VERSION 5.8 ;
BUSBITCHARS "[]" ;
DIVIDERCHAR "/" ;

VIA PYL1_C_0
  VIARULE PYL1_C ;
  CUTSIZE 0.17 0.17 ;
  LAYERS poly licon1 li1 ;
  CUTSPACING 0.17 0.17 ;
  ENCLOSURE 0.08 0.08 0.08 0.08 ;
  ROWCOL 1 1 ;
END PYL1_C_0

VIA PYL1_C_1
  VIARULE PYL1_C ;
  CUTSIZE 0.17 0.17 ;
  LAYERS poly licon1 li1 ;
  CUTSPACING 0.17 0.17 ;
  ENCLOSURE 0.08 0.08 0.08 0.08 ;
  ROWCOL 1 23 ;
END PYL1_C_1

VIA PYL1_C_2
  VIARULE PYL1_C ;
  CUTSIZE 0.17 0.17 ;
  LAYERS poly licon1 li1 ;
  CUTSPACING 0.17 0.17 ;
  ENCLOSURE 0.08 0.08 0.08 0.08 ;
  ROWCOL 1 7 ;
END PYL1_C_2

VIA PYL1_C_3
  VIARULE PYL1_C ;
  CUTSIZE 0.17 0.17 ;
  LAYERS poly licon1 li1 ;
  CUTSPACING 0.17 0.17 ;
  ENCLOSURE 0.08 0.08 0.08 0.08 ;
  ROWCOL 1 17 ;
END PYL1_C_3

VIA PYL1_C_4
  VIARULE PYL1_C ;
  CUTSIZE 0.17 0.17 ;
  LAYERS poly licon1 li1 ;
  CUTSPACING 0.17 0.17 ;
  ENCLOSURE 0.08 0.08 0.08 0.08 ;
  ROWCOL 1 21 ;
END PYL1_C_4

VIA PYL1_C_5
  VIARULE PYL1_C ;
  CUTSIZE 0.17 0.17 ;
  LAYERS poly licon1 li1 ;
  CUTSPACING 0.17 0.17 ;
  ENCLOSURE 0.08 0.08 0.08 0.08 ;
  ROWCOL 1 8 ;
END PYL1_C_5

VIA PYL1_C_6
  VIARULE PYL1_C ;
  CUTSIZE 0.17 0.17 ;
  LAYERS poly licon1 li1 ;
  CUTSPACING 0.17 0.17 ;
  ENCLOSURE 0.08 0.08 0.08 0.08 ;
  ROWCOL 1 10 ;
END PYL1_C_6

VIA PYL1_C_7
  VIARULE PYL1_C ;
  CUTSIZE 0.17 0.17 ;
  LAYERS poly licon1 li1 ;
  CUTSPACING 0.17 0.17 ;
  ENCLOSURE 0.08 0.08 0.08 0.08 ;
  ROWCOL 1 6 ;
END PYL1_C_7

VIA PYL1_C_8
  VIARULE PYL1_C ;
  CUTSIZE 0.17 0.17 ;
  LAYERS poly licon1 li1 ;
  CUTSPACING 0.17 0.17 ;
  ENCLOSURE 0.08 0.08 0.08 0.08 ;
  ROWCOL 1 1 ;
END PYL1_C_8

VIA PYL1_C_9
  VIARULE PYL1_C ;
  CUTSIZE 0.17 0.17 ;
  LAYERS poly licon1 li1 ;
  CUTSPACING 0.17 0.17 ;
  ENCLOSURE 0.08 0.08 0.08 0.08 ;
  ROWCOL 1 3 ;
END PYL1_C_9

VIA PYL1_C_10
  VIARULE PYL1_C ;
  CUTSIZE 0.17 0.17 ;
  LAYERS poly licon1 li1 ;
  CUTSPACING 0.19 0.19 ;
  ENCLOSURE 0.08 0.08 0.08 0.08 ;
  ROWCOL 1 2 ;
END PYL1_C_10

VIA PYL1_C_11
  VIARULE PYL1_C ;
  CUTSIZE 0.17 0.17 ;
  LAYERS poly licon1 li1 ;
  CUTSPACING 0.17 0.17 ;
  ENCLOSURE 0.08 0.08 0.08 0.08 ;
  ROWCOL 1 5 ;
END PYL1_C_11

VIA PYL1_C_12
  VIARULE PYL1_C ;
  CUTSIZE 0.17 0.17 ;
  LAYERS poly licon1 li1 ;
  CUTSPACING 0.17 0.17 ;
  ENCLOSURE 0.08 0.08 0.08 0.08 ;
  ROWCOL 1 14 ;
END PYL1_C_12

VIA PYL1_C_13
  VIARULE PYL1_C ;
  CUTSIZE 0.17 0.17 ;
  LAYERS poly licon1 li1 ;
  CUTSPACING 0.17 0.17 ;
  ENCLOSURE 0.08 0.08 0.08 0.08 ;
  ROWCOL 1 90 ;
END PYL1_C_13

VIA PYL1_C_14
  VIARULE PYL1_C ;
  CUTSIZE 0.17 0.17 ;
  LAYERS poly licon1 li1 ;
  CUTSPACING 0.17 0.17 ;
  ENCLOSURE 0.08 0.08 0.08 0.08 ;
  ROWCOL 1 4 ;
END PYL1_C_14

VIA PYL1_C_15
  VIARULE PYL1_C ;
  CUTSIZE 0.17 0.17 ;
  LAYERS poly licon1 li1 ;
  CUTSPACING 0.17 0.17 ;
  ENCLOSURE 0.08 0.08 0.08 0.08 ;
  ROWCOL 2 1 ;
END PYL1_C_15

VIA L1M1_C_16
  VIARULE L1M1_C ;
  CUTSIZE 0.17 0.17 ;
  LAYERS li1 mcon met1 ;
  CUTSPACING 0.19 0.19 ;
  ENCLOSURE 0 0 0.06 0.06 ;
  ROWCOL 1 1 ;
END L1M1_C_16

VIA L1M1_C_17
  VIARULE L1M1_C ;
  CUTSIZE 0.17 0.17 ;
  LAYERS li1 mcon met1 ;
  CUTSPACING 0.19 0.19 ;
  ENCLOSURE 0 0 0.06 0.06 ;
  ROWCOL 4 5 ;
END L1M1_C_17

VIA L1M1_C_18
  VIARULE L1M1_C ;
  CUTSIZE 0.17 0.17 ;
  LAYERS li1 mcon met1 ;
  CUTSPACING 0.19 0.19 ;
  ENCLOSURE 0 0 0.06 0.06 ;
  ROWCOL 1 20 ;
END L1M1_C_18

VIA L1M1_C_19
  VIARULE L1M1_C ;
  CUTSIZE 0.17 0.17 ;
  LAYERS li1 mcon met1 ;
  CUTSPACING 0.19 0.19 ;
  ENCLOSURE 0 0 0.06 0.06 ;
  ROWCOL 1 6 ;
END L1M1_C_19

VIA L1M1_C_20
  VIARULE L1M1_C ;
  CUTSIZE 0.17 0.17 ;
  LAYERS li1 mcon met1 ;
  CUTSPACING 0.19 0.19 ;
  ENCLOSURE 0 0 0.06 0.06 ;
  ROWCOL 1 8 ;
END L1M1_C_20

VIA L1M1_C_21
  VIARULE L1M1_C ;
  CUTSIZE 0.17 0.17 ;
  LAYERS li1 mcon met1 ;
  CUTSPACING 0.19 0.19 ;
  ENCLOSURE 0 0 0.06 0.06 ;
  ROWCOL 1 3 ;
END L1M1_C_21

VIA L1M1_C_22
  VIARULE L1M1_C ;
  CUTSIZE 0.17 0.17 ;
  LAYERS li1 mcon met1 ;
  CUTSPACING 0.19 0.19 ;
  ENCLOSURE 0 0 0.06 0.06 ;
  ROWCOL 1 12 ;
END L1M1_C_22

VIA L1M1_C_23
  VIARULE L1M1_C ;
  CUTSIZE 0.17 0.17 ;
  LAYERS li1 mcon met1 ;
  CUTSPACING 0.19 0.19 ;
  ENCLOSURE 0 0 0.06 0.06 ;
  ROWCOL 1 4 ;
END L1M1_C_23

VIA L1M1_C_24
  VIARULE L1M1_C ;
  CUTSIZE 0.17 0.17 ;
  LAYERS li1 mcon met1 ;
  CUTSPACING 0.19 0.19 ;
  ENCLOSURE 0 0 0.06 0.06 ;
  ROWCOL 1 85 ;
END L1M1_C_24

VIA L1M1_C_25
  VIARULE L1M1_C ;
  CUTSIZE 0.17 0.17 ;
  LAYERS li1 mcon met1 ;
  CUTSPACING 0.19 0.19 ;
  ENCLOSURE 0 0 0.06 0.06 ;
  ROWCOL 3 1 ;
END L1M1_C_25

VIA L1M1_C_26
  VIARULE L1M1_C ;
  CUTSIZE 0.17 0.17 ;
  LAYERS li1 mcon met1 ;
  CUTSPACING 0.19 0.19 ;
  ENCLOSURE 0 0 0.06 0.06 ;
  ROWCOL 1 2 ;
END L1M1_C_26

VIA L1M1_C_27
  VIARULE L1M1_C ;
  CUTSIZE 0.17 0.17 ;
  LAYERS li1 mcon met1 ;
  CUTSPACING 0.19 0.19 ;
  ENCLOSURE 0 0 0.06 0.06 ;
  ROWCOL 4 1 ;
END L1M1_C_27

VIA L1M1_C_28
  VIARULE L1M1_C ;
  CUTSIZE 0.17 0.17 ;
  LAYERS li1 mcon met1 ;
  CUTSPACING 0.19 0.19 ;
  ENCLOSURE 0 0 0.06 0.06 ;
  ROWCOL 2 2 ;
END L1M1_C_28

VIA L1M1_C_29
  VIARULE L1M1_C ;
  CUTSIZE 0.17 0.17 ;
  LAYERS li1 mcon met1 ;
  CUTSPACING 0.19 0.19 ;
  ENCLOSURE 0 0 0.06 0.06 ;
  ROWCOL 2 4 ;
END L1M1_C_29

VIA L1M1_C_30
  VIARULE L1M1_C ;
  CUTSIZE 0.17 0.17 ;
  LAYERS li1 mcon met1 ;
  CUTSPACING 0.19 0.19 ;
  ENCLOSURE 0 0 0.06 0.06 ;
  ROWCOL 1 1 ;
END L1M1_C_30

VIA L1M1_C_31
  VIARULE L1M1_C ;
  CUTSIZE 0.17 0.17 ;
  LAYERS li1 mcon met1 ;
  CUTSPACING 0.19 0.19 ;
  ENCLOSURE 0 0 0.06 0.06 ;
  ROWCOL 2 1 ;
END L1M1_C_31

VIA L1M1_C_32
  VIARULE L1M1_C ;
  CUTSIZE 0.17 0.17 ;
  LAYERS li1 mcon met1 ;
  CUTSPACING 0.19 0.19 ;
  ENCLOSURE 0 0 0.06 0.06 ;
  ROWCOL 2 18 ;
END L1M1_C_32

VIA L1M1_C_33
  VIARULE L1M1_C ;
  CUTSIZE 0.17 0.17 ;
  LAYERS li1 mcon met1 ;
  CUTSPACING 0.19 0.19 ;
  ENCLOSURE 0 0 0.06 0.06 ;
  ROWCOL 1 7 ;
END L1M1_C_33

VIA M1M2_C_34
  VIARULE M1M2_C ;
  CUTSIZE 0.15 0.15 ;
  LAYERS met1 via met2 ;
  CUTSPACING 0.17 0.17 ;
  ENCLOSURE 0.085 0.085 0.085 0.085 ;
  ROWCOL 1 1 ;
END M1M2_C_34

VIA M1M2_C_35
  VIARULE M1M2_C ;
  CUTSIZE 0.15 0.15 ;
  LAYERS met1 via met2 ;
  CUTSPACING 0.17 0.17 ;
  ENCLOSURE 0.085 0.085 0.085 0.085 ;
  ROWCOL 20 2 ;
END M1M2_C_35

VIA M1M2_C_36
  VIARULE M1M2_C ;
  CUTSIZE 0.15 0.15 ;
  LAYERS met1 via met2 ;
  CUTSPACING 0.17 0.17 ;
  ENCLOSURE 0.085 0.085 0.085 0.085 ;
  ROWCOL 10 2 ;
END M1M2_C_36

VIA M1M2_C_37
  VIARULE M1M2_C ;
  CUTSIZE 0.15 0.15 ;
  LAYERS met1 via met2 ;
  CUTSPACING 0.17 0.17 ;
  ENCLOSURE 0.085 0.085 0.085 0.085 ;
  ROWCOL 14 1 ;
END M1M2_C_37

VIA M1M2_C_38
  VIARULE M1M2_C ;
  CUTSIZE 0.15 0.15 ;
  LAYERS met1 via met2 ;
  CUTSPACING 0.17 0.17 ;
  ENCLOSURE 0.085 0.085 0.085 0.085 ;
  ROWCOL 16 8 ;
END M1M2_C_38

VIA M1M2_C_39
  VIARULE M1M2_C ;
  CUTSIZE 0.15 0.15 ;
  LAYERS met1 via met2 ;
  CUTSPACING 0.17 0.17 ;
  ENCLOSURE 0.085 0.085 0.085 0.085 ;
  ROWCOL 3 5 ;
END M1M2_C_39

VIA M1M2_C_40
  VIARULE M1M2_C ;
  CUTSIZE 0.15 0.15 ;
  LAYERS met1 via met2 ;
  CUTSPACING 0.17 0.17 ;
  ENCLOSURE 0.085 0.085 0.085 0.085 ;
  ROWCOL 5 5 ;
END M1M2_C_40

VIA M1M2_C_41
  VIARULE M1M2_C ;
  CUTSIZE 0.15 0.15 ;
  LAYERS met1 via met2 ;
  CUTSPACING 0.17 0.17 ;
  ENCLOSURE 0.085 0.085 0.085 0.085 ;
  ROWCOL 1 21 ;
END M1M2_C_41

VIA M1M2_C_42
  VIARULE M1M2_C ;
  CUTSIZE 0.15 0.15 ;
  LAYERS met1 via met2 ;
  CUTSPACING 0.17 0.17 ;
  ENCLOSURE 0.085 0.085 0.085 0.085 ;
  ROWCOL 20 1 ;
END M1M2_C_42

VIA M1M2_C_43
  VIARULE M1M2_C ;
  CUTSIZE 0.15 0.15 ;
  LAYERS met1 via met2 ;
  CUTSPACING 0.17 0.17 ;
  ENCLOSURE 0.085 0.085 0.085 0.085 ;
  ROWCOL 7 1 ;
END M1M2_C_43

VIA M1M2_C_44
  VIARULE M1M2_C ;
  CUTSIZE 0.15 0.15 ;
  LAYERS met1 via met2 ;
  CUTSPACING 0.17 0.17 ;
  ENCLOSURE 0.085 0.085 0.085 0.085 ;
  ROWCOL 9 3 ;
END M1M2_C_44

VIA M1M2_C_45
  VIARULE M1M2_C ;
  CUTSIZE 0.15 0.15 ;
  LAYERS met1 via met2 ;
  CUTSPACING 0.17 0.17 ;
  ENCLOSURE 0.085 0.085 0.085 0.085 ;
  ROWCOL 15 1 ;
END M1M2_C_45

VIA M1M2_C_46
  VIARULE M1M2_C ;
  CUTSIZE 0.15 0.15 ;
  LAYERS met1 via met2 ;
  CUTSPACING 0.17 0.17 ;
  ENCLOSURE 0.085 0.085 0.085 0.085 ;
  ROWCOL 5 2 ;
END M1M2_C_46

VIA M1M2_C_47
  VIARULE M1M2_C ;
  CUTSIZE 0.15 0.15 ;
  LAYERS met1 via met2 ;
  CUTSPACING 0.17 0.17 ;
  ENCLOSURE 0.085 0.085 0.085 0.085 ;
  ROWCOL 1 8 ;
END M1M2_C_47

VIA M1M2_C_48
  VIARULE M1M2_C ;
  CUTSIZE 0.15 0.15 ;
  LAYERS met1 via met2 ;
  CUTSPACING 0.17 0.17 ;
  ENCLOSURE 0.085 0.085 0.085 0.085 ;
  ROWCOL 8 1 ;
END M1M2_C_48

VIA M1M2_C_49
  VIARULE M1M2_C ;
  CUTSIZE 0.15 0.15 ;
  LAYERS met1 via met2 ;
  CUTSPACING 0.17 0.17 ;
  ENCLOSURE 0.085 0.085 0.085 0.085 ;
  ROWCOL 7 3 ;
END M1M2_C_49

VIA M1M2_C_50
  VIARULE M1M2_C ;
  CUTSIZE 0.15 0.15 ;
  LAYERS met1 via met2 ;
  CUTSPACING 0.21 0.21 ;
  ENCLOSURE 0.085 0.085 0.085 0.085 ;
  ROWCOL 2 1 ;
END M1M2_C_50

VIA M1M2_C_51
  VIARULE M1M2_C ;
  CUTSIZE 0.15 0.15 ;
  LAYERS met1 via met2 ;
  CUTSPACING 0.17 0.17 ;
  ENCLOSURE 0.085 0.085 0.085 0.085 ;
  ROWCOL 3 3 ;
END M1M2_C_51

VIA M1M2_C_52
  VIARULE M1M2_C ;
  CUTSIZE 0.15 0.15 ;
  LAYERS met1 via met2 ;
  CUTSPACING 0.17 0.17 ;
  ENCLOSURE 0.085 0.085 0.085 0.085 ;
  ROWCOL 5 3 ;
END M1M2_C_52

VIA M1M2_C_53
  VIARULE M1M2_C ;
  CUTSIZE 0.15 0.15 ;
  LAYERS met1 via met2 ;
  CUTSPACING 0.17 0.17 ;
  ENCLOSURE 0.085 0.085 0.085 0.085 ;
  ROWCOL 5 8 ;
END M1M2_C_53

VIA M1M2_C_54
  VIARULE M1M2_C ;
  CUTSIZE 0.15 0.15 ;
  LAYERS met1 via met2 ;
  CUTSPACING 0.17 0.17 ;
  ENCLOSURE 0.085 0.085 0.085 0.085 ;
  ROWCOL 14 7 ;
END M1M2_C_54

VIA M1M2_C_55
  VIARULE M1M2_C ;
  CUTSIZE 0.15 0.15 ;
  LAYERS met1 via met2 ;
  CUTSPACING 0.17 0.17 ;
  ENCLOSURE 0.085 0.085 0.085 0.085 ;
  ROWCOL 19 7 ;
END M1M2_C_55

VIA M1M2_C_56
  VIARULE M1M2_C ;
  CUTSIZE 0.15 0.15 ;
  LAYERS met1 via met2 ;
  CUTSPACING 0.17 0.17 ;
  ENCLOSURE 0.085 0.085 0.085 0.085 ;
  ROWCOL 20 7 ;
END M1M2_C_56

VIA M1M2_C_57
  VIARULE M1M2_C ;
  CUTSIZE 0.15 0.15 ;
  LAYERS met1 via met2 ;
  CUTSPACING 0.17 0.17 ;
  ENCLOSURE 0.085 0.085 0.085 0.085 ;
  ROWCOL 15 10 ;
END M1M2_C_57

VIA M1M2_C_58
  VIARULE M1M2_C ;
  CUTSIZE 0.15 0.15 ;
  LAYERS met1 via met2 ;
  CUTSPACING 0.17 0.17 ;
  ENCLOSURE 0.085 0.085 0.085 0.085 ;
  ROWCOL 4 1 ;
END M1M2_C_58

VIA M1M2_C_59
  VIARULE M1M2_C ;
  CUTSIZE 0.15 0.15 ;
  LAYERS met1 via met2 ;
  CUTSPACING 0.17 0.17 ;
  ENCLOSURE 0.085 0.085 0.085 0.085 ;
  ROWCOL 1 3 ;
END M1M2_C_59

VIA M1M2_C_60
  VIARULE M1M2_C ;
  CUTSIZE 0.15 0.15 ;
  LAYERS met1 via met2 ;
  CUTSPACING 0.17 0.17 ;
  ENCLOSURE 0.085 0.085 0.085 0.085 ;
  ROWCOL 3 2 ;
END M1M2_C_60

VIA M1M2_C_61
  VIARULE M1M2_C ;
  CUTSIZE 0.15 0.15 ;
  LAYERS met1 via met2 ;
  CUTSPACING 0.17 0.17 ;
  ENCLOSURE 0.085 0.085 0.085 0.085 ;
  ROWCOL 6 8 ;
END M1M2_C_61

VIA M1M2_C_62
  VIARULE M1M2_C ;
  CUTSIZE 0.15 0.15 ;
  LAYERS met1 via met2 ;
  CUTSPACING 0.17 0.17 ;
  ENCLOSURE 0.085 0.085 0.085 0.085 ;
  ROWCOL 2 2 ;
END M1M2_C_62

VIA M1M2_C_63
  VIARULE M1M2_C ;
  CUTSIZE 0.15 0.15 ;
  LAYERS met1 via met2 ;
  CUTSPACING 0.17 0.17 ;
  ENCLOSURE 0.085 0.085 0.085 0.085 ;
  ROWCOL 3 1 ;
END M1M2_C_63

VIA M1M2_C_64
  VIARULE M1M2_C ;
  CUTSIZE 0.15 0.15 ;
  LAYERS met1 via met2 ;
  CUTSPACING 0.17 0.17 ;
  ENCLOSURE 0.085 0.085 0.085 0.085 ;
  ROWCOL 6 1 ;
END M1M2_C_64

VIA M1M2_C_65
  VIARULE M1M2_C ;
  CUTSIZE 0.15 0.15 ;
  LAYERS met1 via met2 ;
  CUTSPACING 0.17 0.17 ;
  ENCLOSURE 0.085 0.085 0.085 0.085 ;
  ROWCOL 1 6 ;
END M1M2_C_65

VIA M1M2_C_66
  VIARULE M1M2_C ;
  CUTSIZE 0.15 0.15 ;
  LAYERS met1 via met2 ;
  CUTSPACING 0.17 0.17 ;
  ENCLOSURE 0.085 0.085 0.085 0.085 ;
  ROWCOL 1 2 ;
END M1M2_C_66

VIA M1M2_C_67
  VIARULE M1M2_C ;
  CUTSIZE 0.15 0.15 ;
  LAYERS met1 via met2 ;
  CUTSPACING 0.17 0.17 ;
  ENCLOSURE 0.085 0.085 0.085 0.085 ;
  ROWCOL 2 1 ;
END M1M2_C_67

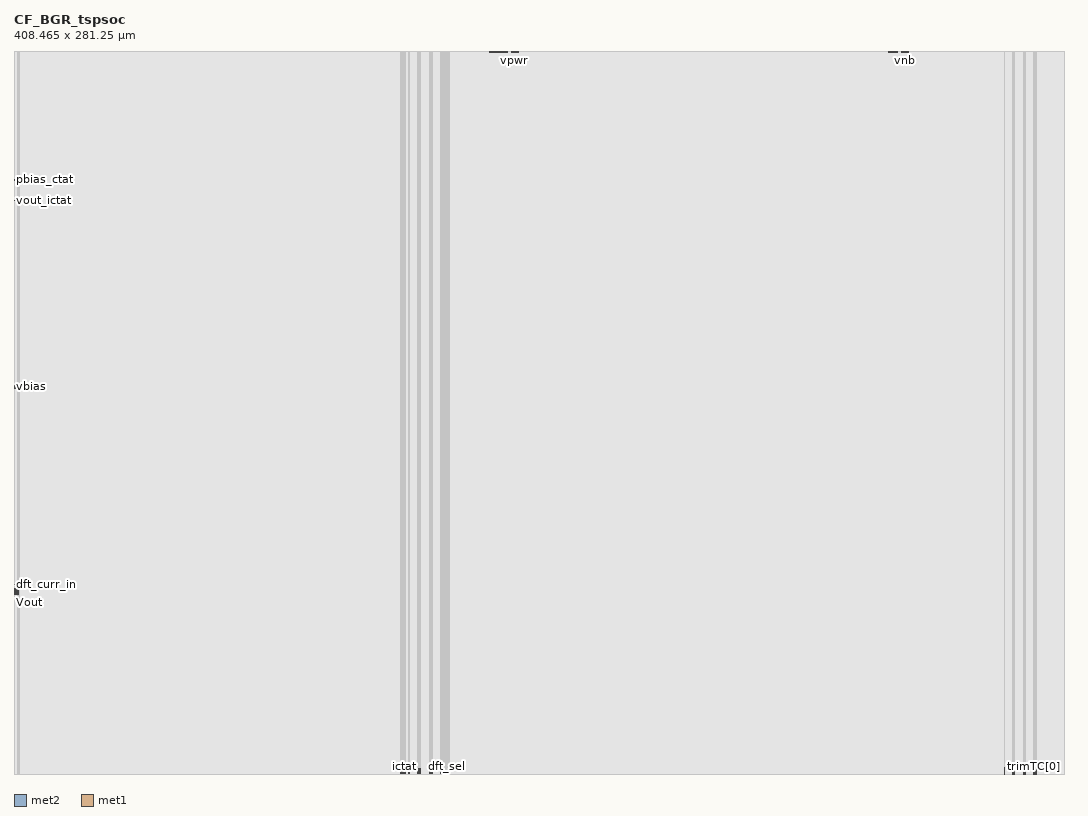
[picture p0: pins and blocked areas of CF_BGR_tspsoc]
MACRO CF_BGR_tspsoc
  ORIGIN 0 0 ;
  SIZE 408.465 BY 281.25 ;
  PIN CurrAbsTrim[5]
    DIRECTION INOUT ;
    USE SIGNAL ;
    PORT
      LAYER met2 ;
        RECT 166.425 0.03 166.565 2.085 ;
    END
  END CurrAbsTrim[5]
  PIN inl_ctrl[2]
    DIRECTION INPUT ;
    USE SIGNAL ;
    PORT
      LAYER met2 ;
        RECT 150.5 0.03 150.64 2.915 ;
    END
  END inl_ctrl[2]
  PIN vout_ictat
    DIRECTION OUTPUT ;
    USE SIGNAL ;
    PORT
      LAYER met2 ;
        RECT 0 223.06 2.075 223.2 ;
    END
  END vout_ictat
  PIN pbias_ctat
    DIRECTION OUTPUT ;
    USE SIGNAL ;
    PORT
      LAYER met2 ;
        RECT 0 231.01 2.075 231.15 ;
    END
  END pbias_ctat
  PIN trimCurr[5]
    DIRECTION INPUT ;
    USE SIGNAL ;
    PORT
      LAYER met2 ;
        RECT 153.295 0.03 153.435 2.085 ;
    END
  END trimCurr[5]
  PIN trimCurr[4]
    DIRECTION INPUT ;
    USE SIGNAL ;
    PORT
      LAYER met2 ;
        RECT 157.055 0.03 157.195 2.085 ;
    END
  END trimCurr[4]
  PIN trimCurr[3]
    DIRECTION INPUT ;
    USE SIGNAL ;
    PORT
      LAYER met2 ;
        RECT 157.425 0.03 157.565 2.085 ;
    END
  END trimCurr[3]
  PIN trimCurr[2]
    DIRECTION INPUT ;
    USE SIGNAL ;
    PORT
      LAYER met2 ;
        RECT 157.795 0.03 157.935 2.085 ;
    END
  END trimCurr[2]
  PIN trimCurr[0]
    DIRECTION INPUT ;
    USE SIGNAL ;
    PORT
      LAYER met2 ;
        RECT 158.165 0.03 158.305 2.085 ;
    END
  END trimCurr[0]
  PIN trimCurr[1]
    DIRECTION INPUT ;
    USE SIGNAL ;
    PORT
      LAYER met2 ;
        RECT 161.555 0.03 161.695 2.085 ;
    END
  END trimCurr[1]
  PIN CurrAbsTrim[0]
    DIRECTION INPUT ;
    USE SIGNAL ;
    PORT
      LAYER met2 ;
        RECT 153.665 0.03 153.805 2.085 ;
    END
  END CurrAbsTrim[0]
  PIN CurrAbsTrim[1]
    DIRECTION INPUT ;
    USE SIGNAL ;
    PORT
      LAYER met2 ;
        RECT 161.925 0.03 162.065 2.085 ;
    END
  END CurrAbsTrim[1]
  PIN CurrAbsTrim[2]
    DIRECTION INPUT ;
    USE SIGNAL ;
    PORT
      LAYER met2 ;
        RECT 162.295 0.03 162.435 2.085 ;
    END
  END CurrAbsTrim[2]
  PIN CurrAbsTrim[3]
    DIRECTION INPUT ;
    USE SIGNAL ;
    PORT
      LAYER met2 ;
        RECT 162.665 0.03 162.805 2.085 ;
    END
  END CurrAbsTrim[3]
  PIN CurrAbsTrim[4]
    DIRECTION INOUT ;
    USE SIGNAL ;
    PORT
      LAYER met2 ;
        RECT 166.055 0.03 166.195 2.085 ;
    END
  END CurrAbsTrim[4]
  PIN mux2sel
    DIRECTION INPUT ;
    USE SIGNAL ;
    PORT
      LAYER met2 ;
        RECT 167.16 0.03 167.3 1.065 ;
    END
  END mux2sel
  PIN mux1sel[0]
    DIRECTION INPUT ;
    USE SIGNAL ;
    PORT
      LAYER met2 ;
        RECT 167.53 0.03 167.67 1.065 ;
    END
  END mux1sel[0]
  PIN mux1sel[1]
    DIRECTION INPUT ;
    USE SIGNAL ;
    PORT
      LAYER met2 ;
        RECT 167.9 0.03 168.04 1.065 ;
    END
  END mux1sel[1]
  PIN dft_sel
    DIRECTION INPUT ;
    USE SIGNAL ;
    PORT
      LAYER met2 ;
        RECT 168.27 0.03 168.41 1.065 ;
    END
  END dft_sel
  PIN pd_ibg
    DIRECTION INPUT ;
    USE SIGNAL ;
    PORT
      LAYER met2 ;
        RECT 168.65 0.03 168.79 1.065 ;
    END
  END pd_ibg
  PIN pd
    DIRECTION INPUT ;
    USE SIGNAL ;
    PORT
      LAYER met2 ;
        RECT 169.095 0.03 169.235 1.065 ;
    END
  END pd
  PIN trimTC[6]
    DIRECTION INPUT ;
    USE SIGNAL ;
    PORT
      LAYER met2 ;
        RECT 385.145 0 385.285 2.375 ;
    END
  END trimTC[6]
  PIN trimTC[5]
    DIRECTION INPUT ;
    USE SIGNAL ;
    PORT
      LAYER met2 ;
        RECT 388.535 0 388.675 2.375 ;
    END
  END trimTC[5]
  PIN trimTC[4]
    DIRECTION INPUT ;
    USE SIGNAL ;
    PORT
      LAYER met2 ;
        RECT 389.18 0 389.32 2.375 ;
    END
  END trimTC[4]
  PIN trimTC[3]
    DIRECTION INPUT ;
    USE SIGNAL ;
    PORT
      LAYER met2 ;
        RECT 392.57 0 392.71 2.375 ;
    END
  END trimTC[3]
  PIN trimTC[2]
    DIRECTION INPUT ;
    USE SIGNAL ;
    PORT
      LAYER met2 ;
        RECT 393.27 0 393.41 2.375 ;
    END
  END trimTC[2]
  PIN trimTC[0]
    DIRECTION INPUT ;
    USE SIGNAL ;
    PORT
      LAYER met2 ;
        RECT 396.66 0 396.8 2.375 ;
    END
  END trimTC[0]
  PIN trimTC[1]
    DIRECTION INPUT ;
    USE SIGNAL ;
    PORT
      LAYER met2 ;
        RECT 397.535 0 397.675 2.375 ;
    END
  END trimTC[1]
  PIN inl_ctrl[0]
    DIRECTION INPUT ;
    USE SIGNAL ;
    PORT
      LAYER met2 ;
        RECT 151.375 0.03 151.515 2.085 ;
    END
  END inl_ctrl[0]
  PIN inl_ctrl[1]
    DIRECTION INPUT ;
    USE SIGNAL ;
    PORT
      LAYER met2 ;
        RECT 150.955 0.03 151.095 2.085 ;
    END
  END inl_ctrl[1]
  PIN vbias_cascode
    DIRECTION OUTPUT ;
    USE SIGNAL ;
    PORT
      LAYER met2 ;
        RECT 0 150.03 2.075 150.17 ;
    END
  END vbias_cascode
  PIN vbias
    DIRECTION OUTPUT ;
    USE SIGNAL ;
    PORT
      LAYER met2 ;
        RECT 0 150.81 2.075 150.95 ;
    END
  END vbias
  PIN dft_curr_in
    DIRECTION INPUT ;
    USE SIGNAL ;
    PORT
      LAYER met2 ;
        RECT 0 73.7 1.495 73.84 ;
    END
  END dft_curr_in
  PIN Vout
    DIRECTION OUTPUT ;
    USE SIGNAL ;
    PORT
      LAYER met2 ;
        RECT 0 69.64 1.75 69.78 ;
    END
  END Vout
  PIN ibg_3uA
    DIRECTION OUTPUT ;
    USE SIGNAL ;
    PORT
      LAYER met2 ;
        RECT 0 70.14 1.75 70.28 ;
    END
  END ibg_3uA
  PIN ibg_2p375uA
    DIRECTION OUTPUT ;
    USE SIGNAL ;
    PORT
      LAYER met2 ;
        RECT 0 70.58 1.75 70.72 ;
    END
  END ibg_2p375uA
  PIN mux1out
    DIRECTION OUTPUT ;
    USE SIGNAL ;
    PORT
      LAYER met2 ;
        RECT 0 71.11 1.75 71.25 ;
    END
  END mux1out
  PIN mux2out
    DIRECTION OUTPUT ;
    USE SIGNAL ;
    PORT
      LAYER met2 ;
        RECT 0 71.905 1.75 72.045 ;
    END
  END mux2out
  PIN ictat
    DIRECTION OUTPUT ;
    USE SIGNAL ;
    PORT
      LAYER met2 ;
        RECT 151.8 0.03 151.94 1.065 ;
    END
  END ictat
  PIN iptat
    DIRECTION OUTPUT ;
    USE SIGNAL ;
    PORT
      LAYER met2 ;
        RECT 152.22 0.03 152.36 1.065 ;
    END
  END iptat
  PIN vpb
    DIRECTION INPUT ;
    USE SIGNAL ;
    PORT
      LAYER met1 ;
        RECT 184.955 280.85 192.08 281.25 ;
    END
  END vpb
  PIN vgnd
    DIRECTION INPUT ;
    USE SIGNAL ;
    PORT
      LAYER met1 ;
        RECT 340.21 280.85 343.78 281.25 ;
    END
  END vgnd
  PIN vnb
    DIRECTION INPUT ;
    USE SIGNAL ;
    PORT
      LAYER met1 ;
        RECT 345.205 280.85 347.975 281.25 ;
    END
  END vnb
  PIN vpwr
    DIRECTION INPUT ;
    USE SIGNAL ;
    PORT
      LAYER met1 ;
        RECT 193.455 280.85 196.235 281.25 ;
    END
  END vpwr
  OBS
    LAYER li1 ;
      RECT 0 0 408.465 281.25 ;
    LAYER met1 ;
      RECT 0 0 184.955 281.25 ;
      RECT 184.955 0 192.08 280.85 ;
      RECT 192.08 0 193.455 281.25 ;
      RECT 193.455 0 196.235 280.85 ;
      RECT 196.235 0 340.21 281.25 ;
      RECT 340.21 0 343.78 280.85 ;
      RECT 343.78 0 345.205 281.25 ;
      RECT 345.205 0 347.975 280.85 ;
      RECT 347.975 0 408.465 281.25 ;
    LAYER met2 ;
      RECT 0 0 1.495 69.64 ;
      RECT 0 69.78 1.495 70.14 ;
      RECT 0 70.28 1.495 70.58 ;
      RECT 0 70.72 1.495 71.11 ;
      RECT 0 71.25 1.495 71.905 ;
      RECT 0 72.045 1.495 73.7 ;
      RECT 0 73.84 1.495 150.03 ;
      RECT 0 150.17 1.495 150.81 ;
      RECT 0 150.95 1.495 223.06 ;
      RECT 0 223.2 1.495 231.01 ;
      RECT 0 231.15 1.495 281.25 ;
      RECT 1.495 0 1.75 69.64 ;
      RECT 1.495 69.78 1.75 70.14 ;
      RECT 1.495 70.28 1.75 70.58 ;
      RECT 1.495 70.72 1.75 71.11 ;
      RECT 1.495 71.25 1.75 71.905 ;
      RECT 1.495 72.045 1.75 150.03 ;
      RECT 1.495 150.17 1.75 150.81 ;
      RECT 1.495 150.95 1.75 223.06 ;
      RECT 1.495 223.2 1.75 231.01 ;
      RECT 1.495 231.15 1.75 281.25 ;
      RECT 1.75 0 2.075 150.03 ;
      RECT 1.75 150.17 2.075 150.81 ;
      RECT 1.75 150.95 2.075 223.06 ;
      RECT 1.75 223.2 2.075 231.01 ;
      RECT 1.75 231.15 2.075 281.25 ;
      RECT 2.075 0 150.5 281.25 ;
      RECT 150.5 0 150.64 0.03 ;
      RECT 150.5 2.915 150.64 281.25 ;
      RECT 150.64 0 150.955 281.25 ;
      RECT 150.955 0 151.095 0.03 ;
      RECT 150.955 2.085 151.095 281.25 ;
      RECT 151.095 0 151.375 281.25 ;
      RECT 151.375 0 151.515 0.03 ;
      RECT 151.375 2.085 151.515 281.25 ;
      RECT 151.515 0 151.8 281.25 ;
      RECT 151.8 0 151.94 0.03 ;
      RECT 151.8 1.065 151.94 281.25 ;
      RECT 151.94 0 152.22 281.25 ;
      RECT 152.22 0 152.36 0.03 ;
      RECT 152.22 1.065 152.36 281.25 ;
      RECT 152.36 0 153.295 281.25 ;
      RECT 153.295 0 153.435 0.03 ;
      RECT 153.295 2.085 153.435 281.25 ;
      RECT 153.435 0 153.665 281.25 ;
      RECT 153.665 0 153.805 0.03 ;
      RECT 153.665 2.085 153.805 281.25 ;
      RECT 153.805 0 157.055 281.25 ;
      RECT 157.055 0 157.195 0.03 ;
      RECT 157.055 2.085 157.195 281.25 ;
      RECT 157.195 0 157.425 281.25 ;
      RECT 157.425 0 157.565 0.03 ;
      RECT 157.425 2.085 157.565 281.25 ;
      RECT 157.565 0 157.795 281.25 ;
      RECT 157.795 0 157.935 0.03 ;
      RECT 157.795 2.085 157.935 281.25 ;
      RECT 157.935 0 158.165 281.25 ;
      RECT 158.165 0 158.305 0.03 ;
      RECT 158.165 2.085 158.305 281.25 ;
      RECT 158.305 0 161.555 281.25 ;
      RECT 161.555 0 161.695 0.03 ;
      RECT 161.555 2.085 161.695 281.25 ;
      RECT 161.695 0 161.925 281.25 ;
      RECT 161.925 0 162.065 0.03 ;
      RECT 161.925 2.085 162.065 281.25 ;
      RECT 162.065 0 162.295 281.25 ;
      RECT 162.295 0 162.435 0.03 ;
      RECT 162.295 2.085 162.435 281.25 ;
      RECT 162.435 0 162.665 281.25 ;
      RECT 162.665 0 162.805 0.03 ;
      RECT 162.665 2.085 162.805 281.25 ;
      RECT 162.805 0 166.055 281.25 ;
      RECT 166.055 0 166.195 0.03 ;
      RECT 166.055 2.085 166.195 281.25 ;
      RECT 166.195 0 166.425 281.25 ;
      RECT 166.425 0 166.565 0.03 ;
      RECT 166.425 2.085 166.565 281.25 ;
      RECT 166.565 0 167.16 281.25 ;
      RECT 167.16 0 167.3 0.03 ;
      RECT 167.16 1.065 167.3 281.25 ;
      RECT 167.3 0 167.53 281.25 ;
      RECT 167.53 0 167.67 0.03 ;
      RECT 167.53 1.065 167.67 281.25 ;
      RECT 167.67 0 167.9 281.25 ;
      RECT 167.9 0 168.04 0.03 ;
      RECT 167.9 1.065 168.04 281.25 ;
      RECT 168.04 0 168.27 281.25 ;
      RECT 168.27 0 168.41 0.03 ;
      RECT 168.27 1.065 168.41 281.25 ;
      RECT 168.41 0 168.65 281.25 ;
      RECT 168.65 0 168.79 0.03 ;
      RECT 168.65 1.065 168.79 281.25 ;
      RECT 168.79 0 169.095 281.25 ;
      RECT 169.095 0 169.235 0.03 ;
      RECT 169.095 1.065 169.235 281.25 ;
      RECT 169.235 0 385.145 281.25 ;
      RECT 385.145 2.375 385.285 281.25 ;
      RECT 385.285 0 388.535 281.25 ;
      RECT 388.535 2.375 388.675 281.25 ;
      RECT 388.675 0 389.18 281.25 ;
      RECT 389.18 2.375 389.32 281.25 ;
      RECT 389.32 0 392.57 281.25 ;
      RECT 392.57 2.375 392.71 281.25 ;
      RECT 392.71 0 393.27 281.25 ;
      RECT 393.27 2.375 393.41 281.25 ;
      RECT 393.41 0 396.66 281.25 ;
      RECT 396.66 2.375 396.8 281.25 ;
      RECT 396.8 0 397.535 281.25 ;
      RECT 397.535 2.375 397.675 281.25 ;
      RECT 397.675 0 408.465 281.25 ;
  END
END CF_BGR_tspsoc

END LIBRARY
